VERSION 5.7 ;
  NOWIREEXTENSIONATPIN ON ;
  DIVIDERCHAR "/" ;
  BUSBITCHARS "[]" ;
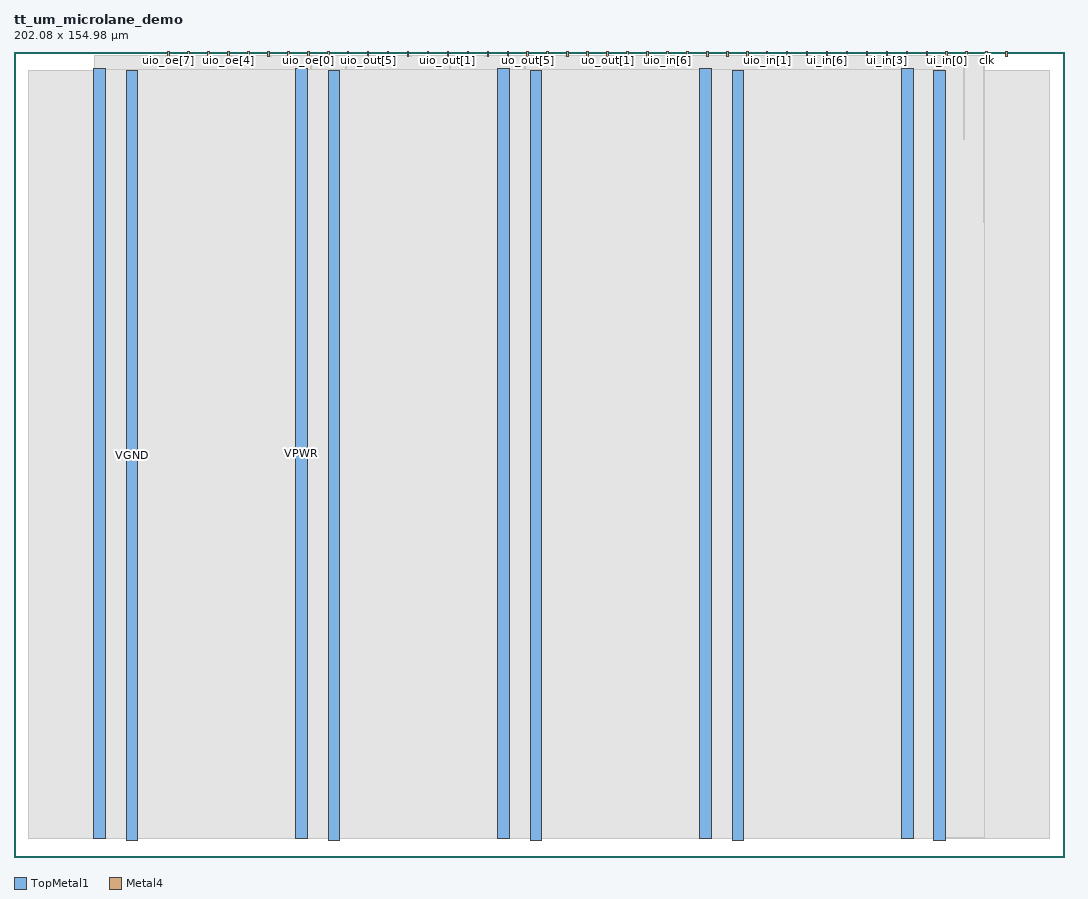
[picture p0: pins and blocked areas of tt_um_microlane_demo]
MACRO tt_um_microlane_demo
  CLASS BLOCK ;
  FOREIGN tt_um_microlane_demo ;
  ORIGIN 0.000 0.000 ;
  SIZE 202.080 BY 154.980 ;
  PIN VPWR
    DIRECTION INOUT ;
    USE POWER ;
    PORT
      LAYER TopMetal1 ;
        RECT 15.380 3.560 17.580 151.830 ;
    END
    PORT
      LAYER TopMetal1 ;
        RECT 54.250 3.560 56.450 151.830 ;
    END
    PORT
      LAYER TopMetal1 ;
        RECT 93.120 3.560 95.320 151.830 ;
    END
    PORT
      LAYER TopMetal1 ;
        RECT 131.990 3.560 134.190 151.830 ;
    END
    PORT
      LAYER TopMetal1 ;
        RECT 170.860 3.560 173.060 151.830 ;
    END
  END VPWR
  PIN VGND
    DIRECTION INOUT ;
    USE GROUND ;
    PORT
      LAYER TopMetal1 ;
        RECT 21.580 3.150 23.780 151.420 ;
    END
    PORT
      LAYER TopMetal1 ;
        RECT 60.450 3.150 62.650 151.420 ;
    END
    PORT
      LAYER TopMetal1 ;
        RECT 99.320 3.150 101.520 151.420 ;
    END
    PORT
      LAYER TopMetal1 ;
        RECT 138.190 3.150 140.390 151.420 ;
    END
    PORT
      LAYER TopMetal1 ;
        RECT 177.060 3.150 179.260 151.420 ;
    END
  END VGND
  PIN ena
    DIRECTION INPUT ;
    USE SIGNAL ;
    PORT
      LAYER Metal4 ;
        RECT 190.890 153.980 191.190 154.980 ;
    END
  END ena
  PIN clk
    DIRECTION INPUT ;
    USE SIGNAL ;
    PORT
      LAYER Metal4 ;
        RECT 187.050 153.980 187.350 154.980 ;
    END
  END clk
  PIN rst_n
    DIRECTION INPUT ;
    USE SIGNAL ;
    PORT
      LAYER Metal4 ;
        RECT 183.210 153.980 183.510 154.980 ;
    END
  END rst_n
  PIN ui_in[0]
    DIRECTION INPUT ;
    USE SIGNAL ;
    PORT
      LAYER Metal4 ;
        RECT 179.370 153.980 179.670 154.980 ;
    END
  END ui_in[0]
  PIN ui_in[1]
    DIRECTION INPUT ;
    USE SIGNAL ;
    PORT
      LAYER Metal4 ;
        RECT 175.530 153.980 175.830 154.980 ;
    END
  END ui_in[1]
  PIN ui_in[2]
    DIRECTION INPUT ;
    USE SIGNAL ;
    PORT
      LAYER Metal4 ;
        RECT 171.690 153.980 171.990 154.980 ;
    END
  END ui_in[2]
  PIN ui_in[3]
    DIRECTION INPUT ;
    USE SIGNAL ;
    PORT
      LAYER Metal4 ;
        RECT 167.850 153.980 168.150 154.980 ;
    END
  END ui_in[3]
  PIN ui_in[4]
    DIRECTION INPUT ;
    USE SIGNAL ;
    PORT
      LAYER Metal4 ;
        RECT 164.010 153.980 164.310 154.980 ;
    END
  END ui_in[4]
  PIN ui_in[5]
    DIRECTION INPUT ;
    USE SIGNAL ;
    PORT
      LAYER Metal4 ;
        RECT 160.170 153.980 160.470 154.980 ;
    END
  END ui_in[5]
  PIN ui_in[6]
    DIRECTION INPUT ;
    USE SIGNAL ;
    PORT
      LAYER Metal4 ;
        RECT 156.330 153.980 156.630 154.980 ;
    END
  END ui_in[6]
  PIN ui_in[7]
    DIRECTION INPUT ;
    USE SIGNAL ;
    PORT
      LAYER Metal4 ;
        RECT 152.490 153.980 152.790 154.980 ;
    END
  END ui_in[7]
  PIN uio_in[0]
    DIRECTION INPUT ;
    USE SIGNAL ;
    PORT
      LAYER Metal4 ;
        RECT 148.650 153.980 148.950 154.980 ;
    END
  END uio_in[0]
  PIN uio_in[1]
    DIRECTION INPUT ;
    USE SIGNAL ;
    PORT
      LAYER Metal4 ;
        RECT 144.810 153.980 145.110 154.980 ;
    END
  END uio_in[1]
  PIN uio_in[2]
    DIRECTION INPUT ;
    USE SIGNAL ;
    PORT
      LAYER Metal4 ;
        RECT 140.970 153.980 141.270 154.980 ;
    END
  END uio_in[2]
  PIN uio_in[3]
    DIRECTION INPUT ;
    USE SIGNAL ;
    PORT
      LAYER Metal4 ;
        RECT 137.130 153.980 137.430 154.980 ;
    END
  END uio_in[3]
  PIN uio_in[4]
    DIRECTION INPUT ;
    USE SIGNAL ;
    PORT
      LAYER Metal4 ;
        RECT 133.290 153.980 133.590 154.980 ;
    END
  END uio_in[4]
  PIN uio_in[5]
    DIRECTION INPUT ;
    USE SIGNAL ;
    PORT
      LAYER Metal4 ;
        RECT 129.450 153.980 129.750 154.980 ;
    END
  END uio_in[5]
  PIN uio_in[6]
    DIRECTION INPUT ;
    USE SIGNAL ;
    PORT
      LAYER Metal4 ;
        RECT 125.610 153.980 125.910 154.980 ;
    END
  END uio_in[6]
  PIN uio_in[7]
    DIRECTION INPUT ;
    USE SIGNAL ;
    PORT
      LAYER Metal4 ;
        RECT 121.770 153.980 122.070 154.980 ;
    END
  END uio_in[7]
  PIN uo_out[0]
    DIRECTION OUTPUT ;
    USE SIGNAL ;
    PORT
      LAYER Metal4 ;
        RECT 117.930 153.980 118.230 154.980 ;
    END
  END uo_out[0]
  PIN uo_out[1]
    DIRECTION OUTPUT ;
    USE SIGNAL ;
    PORT
      LAYER Metal4 ;
        RECT 114.090 153.980 114.390 154.980 ;
    END
  END uo_out[1]
  PIN uo_out[2]
    DIRECTION OUTPUT ;
    USE SIGNAL ;
    PORT
      LAYER Metal4 ;
        RECT 110.250 153.980 110.550 154.980 ;
    END
  END uo_out[2]
  PIN uo_out[3]
    DIRECTION OUTPUT ;
    USE SIGNAL ;
    PORT
      LAYER Metal4 ;
        RECT 106.410 153.980 106.710 154.980 ;
    END
  END uo_out[3]
  PIN uo_out[4]
    DIRECTION OUTPUT ;
    USE SIGNAL ;
    PORT
      LAYER Metal4 ;
        RECT 102.570 153.980 102.870 154.980 ;
    END
  END uo_out[4]
  PIN uo_out[5]
    DIRECTION OUTPUT ;
    USE SIGNAL ;
    PORT
      LAYER Metal4 ;
        RECT 98.730 153.980 99.030 154.980 ;
    END
  END uo_out[5]
  PIN uo_out[6]
    DIRECTION OUTPUT ;
    USE SIGNAL ;
    PORT
      LAYER Metal4 ;
        RECT 94.890 153.980 95.190 154.980 ;
    END
  END uo_out[6]
  PIN uo_out[7]
    DIRECTION OUTPUT ;
    USE SIGNAL ;
    PORT
      LAYER Metal4 ;
        RECT 91.050 153.980 91.350 154.980 ;
    END
  END uo_out[7]
  PIN uio_out[0]
    DIRECTION OUTPUT ;
    USE SIGNAL ;
    PORT
      LAYER Metal4 ;
        RECT 87.210 153.980 87.510 154.980 ;
    END
  END uio_out[0]
  PIN uio_out[1]
    DIRECTION OUTPUT ;
    USE SIGNAL ;
    PORT
      LAYER Metal4 ;
        RECT 83.370 153.980 83.670 154.980 ;
    END
  END uio_out[1]
  PIN uio_out[2]
    DIRECTION OUTPUT ;
    USE SIGNAL ;
    PORT
      LAYER Metal4 ;
        RECT 79.530 153.980 79.830 154.980 ;
    END
  END uio_out[2]
  PIN uio_out[3]
    DIRECTION OUTPUT ;
    USE SIGNAL ;
    PORT
      LAYER Metal4 ;
        RECT 75.690 153.980 75.990 154.980 ;
    END
  END uio_out[3]
  PIN uio_out[4]
    DIRECTION OUTPUT ;
    USE SIGNAL ;
    PORT
      LAYER Metal4 ;
        RECT 71.850 153.980 72.150 154.980 ;
    END
  END uio_out[4]
  PIN uio_out[5]
    DIRECTION OUTPUT ;
    USE SIGNAL ;
    PORT
      LAYER Metal4 ;
        RECT 68.010 153.980 68.310 154.980 ;
    END
  END uio_out[5]
  PIN uio_out[6]
    DIRECTION OUTPUT ;
    USE SIGNAL ;
    PORT
      LAYER Metal4 ;
        RECT 64.170 153.980 64.470 154.980 ;
    END
  END uio_out[6]
  PIN uio_out[7]
    DIRECTION OUTPUT ;
    USE SIGNAL ;
    PORT
      LAYER Metal4 ;
        RECT 60.330 153.980 60.630 154.980 ;
    END
  END uio_out[7]
  PIN uio_oe[0]
    DIRECTION OUTPUT ;
    USE SIGNAL ;
    PORT
      LAYER Metal4 ;
        RECT 56.490 153.980 56.790 154.980 ;
    END
  END uio_oe[0]
  PIN uio_oe[1]
    DIRECTION OUTPUT ;
    USE SIGNAL ;
    PORT
      LAYER Metal4 ;
        RECT 52.650 153.980 52.950 154.980 ;
    END
  END uio_oe[1]
  PIN uio_oe[2]
    DIRECTION OUTPUT ;
    USE SIGNAL ;
    PORT
      LAYER Metal4 ;
        RECT 48.810 153.980 49.110 154.980 ;
    END
  END uio_oe[2]
  PIN uio_oe[3]
    DIRECTION OUTPUT ;
    USE SIGNAL ;
    PORT
      LAYER Metal4 ;
        RECT 44.970 153.980 45.270 154.980 ;
    END
  END uio_oe[3]
  PIN uio_oe[4]
    DIRECTION OUTPUT ;
    USE SIGNAL ;
    PORT
      LAYER Metal4 ;
        RECT 41.130 153.980 41.430 154.980 ;
    END
  END uio_oe[4]
  PIN uio_oe[5]
    DIRECTION OUTPUT ;
    USE SIGNAL ;
    PORT
      LAYER Metal4 ;
        RECT 37.290 153.980 37.590 154.980 ;
    END
  END uio_oe[5]
  PIN uio_oe[6]
    DIRECTION OUTPUT ;
    USE SIGNAL ;
    PORT
      LAYER Metal4 ;
        RECT 33.450 153.980 33.750 154.980 ;
    END
  END uio_oe[6]
  PIN uio_oe[7]
    DIRECTION OUTPUT ;
    USE SIGNAL ;
    PORT
      LAYER Metal4 ;
        RECT 29.610 153.980 29.910 154.980 ;
    END
  END uio_oe[7]
  OBS
      LAYER GatPoly ;
        RECT 2.880 3.630 199.200 151.350 ;
      LAYER Metal1 ;
        RECT 2.880 3.560 199.200 151.420 ;
      LAYER Metal2 ;
        RECT 15.560 3.635 179.080 154.285 ;
      LAYER Metal3 ;
        RECT 15.515 3.680 186.865 154.320 ;
      LAYER Metal4 ;
        RECT 15.560 7.415 17.400 7.705 ;
        RECT 54.430 7.415 56.270 7.705 ;
        RECT 93.300 7.415 95.140 7.705 ;
        RECT 132.170 7.415 134.010 7.705 ;
        RECT 171.040 7.415 172.880 7.705 ;
        RECT 15.560 14.975 17.400 15.265 ;
        RECT 54.430 14.975 56.270 15.265 ;
        RECT 93.300 14.975 95.140 15.265 ;
        RECT 132.170 14.975 134.010 15.265 ;
        RECT 171.040 14.975 172.880 15.265 ;
        RECT 15.560 22.535 17.400 22.825 ;
        RECT 54.430 22.535 56.270 22.825 ;
        RECT 93.300 22.535 95.140 22.825 ;
        RECT 132.170 22.535 134.010 22.825 ;
        RECT 171.040 22.535 172.880 22.825 ;
        RECT 15.560 30.095 17.400 30.385 ;
        RECT 54.430 30.095 56.270 30.385 ;
        RECT 93.300 30.095 95.140 30.385 ;
        RECT 132.170 30.095 134.010 30.385 ;
        RECT 171.040 30.095 172.880 30.385 ;
        RECT 15.560 37.655 17.400 37.945 ;
        RECT 54.430 37.655 56.270 37.945 ;
        RECT 93.300 37.655 95.140 37.945 ;
        RECT 132.170 37.655 134.010 37.945 ;
        RECT 171.040 37.655 172.880 37.945 ;
        RECT 15.560 45.215 17.400 45.505 ;
        RECT 54.430 45.215 56.270 45.505 ;
        RECT 93.300 45.215 95.140 45.505 ;
        RECT 132.170 45.215 134.010 45.505 ;
        RECT 171.040 45.215 172.880 45.505 ;
        RECT 15.560 52.775 17.400 53.065 ;
        RECT 54.430 52.775 56.270 53.065 ;
        RECT 93.300 52.775 95.140 53.065 ;
        RECT 132.170 52.775 134.010 53.065 ;
        RECT 171.040 52.775 172.880 53.065 ;
        RECT 15.560 60.335 17.400 60.625 ;
        RECT 54.430 60.335 56.270 60.625 ;
        RECT 93.300 60.335 95.140 60.625 ;
        RECT 132.170 60.335 134.010 60.625 ;
        RECT 171.040 60.335 172.880 60.625 ;
        RECT 15.560 67.895 17.400 68.185 ;
        RECT 54.430 67.895 56.270 68.185 ;
        RECT 93.300 67.895 95.140 68.185 ;
        RECT 132.170 67.895 134.010 68.185 ;
        RECT 171.040 67.895 172.880 68.185 ;
        RECT 15.560 75.455 17.400 75.745 ;
        RECT 54.430 75.455 56.270 75.745 ;
        RECT 93.300 75.455 95.140 75.745 ;
        RECT 132.170 75.455 134.010 75.745 ;
        RECT 171.040 75.455 172.880 75.745 ;
        RECT 15.560 83.015 17.400 83.305 ;
        RECT 54.430 83.015 56.270 83.305 ;
        RECT 93.300 83.015 95.140 83.305 ;
        RECT 132.170 83.015 134.010 83.305 ;
        RECT 171.040 83.015 172.880 83.305 ;
        RECT 15.560 90.575 17.400 90.865 ;
        RECT 54.430 90.575 56.270 90.865 ;
        RECT 93.300 90.575 95.140 90.865 ;
        RECT 132.170 90.575 134.010 90.865 ;
        RECT 171.040 90.575 172.880 90.865 ;
        RECT 15.560 98.135 17.400 98.425 ;
        RECT 54.430 98.135 56.270 98.425 ;
        RECT 93.300 98.135 95.140 98.425 ;
        RECT 132.170 98.135 134.010 98.425 ;
        RECT 171.040 98.135 172.880 98.425 ;
        RECT 15.560 105.695 17.400 105.985 ;
        RECT 54.430 105.695 56.270 105.985 ;
        RECT 93.300 105.695 95.140 105.985 ;
        RECT 132.170 105.695 134.010 105.985 ;
        RECT 171.040 105.695 172.880 105.985 ;
        RECT 15.560 113.255 17.400 113.545 ;
        RECT 54.430 113.255 56.270 113.545 ;
        RECT 93.300 113.255 95.140 113.545 ;
        RECT 132.170 113.255 134.010 113.545 ;
        RECT 171.040 113.255 172.880 113.545 ;
        RECT 15.560 120.815 17.400 121.105 ;
        RECT 54.430 120.815 56.270 121.105 ;
        RECT 93.300 120.815 95.140 121.105 ;
        RECT 132.170 120.815 134.010 121.105 ;
        RECT 171.040 120.815 172.880 121.105 ;
        RECT 15.560 128.375 17.400 128.665 ;
        RECT 54.430 128.375 56.270 128.665 ;
        RECT 93.300 128.375 95.140 128.665 ;
        RECT 132.170 128.375 134.010 128.665 ;
        RECT 171.040 128.375 172.880 128.665 ;
        RECT 15.560 135.935 17.400 136.225 ;
        RECT 54.430 135.935 56.270 136.225 ;
        RECT 93.300 135.935 95.140 136.225 ;
        RECT 132.170 135.935 134.010 136.225 ;
        RECT 171.040 135.935 172.880 136.225 ;
        RECT 15.560 143.495 17.400 143.785 ;
        RECT 54.430 143.495 56.270 143.785 ;
        RECT 93.300 143.495 95.140 143.785 ;
        RECT 132.170 143.495 134.010 143.785 ;
        RECT 171.040 143.495 172.880 143.785 ;
        RECT 15.560 151.055 17.400 151.345 ;
        RECT 54.430 151.055 56.270 151.345 ;
        RECT 93.300 151.055 95.140 151.345 ;
        RECT 132.170 151.055 134.010 151.345 ;
        RECT 171.040 151.055 172.880 151.345 ;
        RECT 21.760 3.635 23.600 3.925 ;
        RECT 60.630 3.635 62.470 3.925 ;
        RECT 99.500 3.635 101.340 3.925 ;
        RECT 138.370 3.635 140.210 3.925 ;
        RECT 177.240 3.635 179.080 3.925 ;
        RECT 21.760 11.195 23.600 11.485 ;
        RECT 60.630 11.195 62.470 11.485 ;
        RECT 99.500 11.195 101.340 11.485 ;
        RECT 138.370 11.195 140.210 11.485 ;
        RECT 177.240 11.195 179.080 11.485 ;
        RECT 21.760 18.755 23.600 19.045 ;
        RECT 60.630 18.755 62.470 19.045 ;
        RECT 99.500 18.755 101.340 19.045 ;
        RECT 138.370 18.755 140.210 19.045 ;
        RECT 177.240 18.755 179.080 19.045 ;
        RECT 21.760 26.315 23.600 26.605 ;
        RECT 60.630 26.315 62.470 26.605 ;
        RECT 99.500 26.315 101.340 26.605 ;
        RECT 138.370 26.315 140.210 26.605 ;
        RECT 177.240 26.315 179.080 26.605 ;
        RECT 21.760 33.875 23.600 34.165 ;
        RECT 60.630 33.875 62.470 34.165 ;
        RECT 99.500 33.875 101.340 34.165 ;
        RECT 138.370 33.875 140.210 34.165 ;
        RECT 177.240 33.875 179.080 34.165 ;
        RECT 21.760 41.435 23.600 41.725 ;
        RECT 60.630 41.435 62.470 41.725 ;
        RECT 99.500 41.435 101.340 41.725 ;
        RECT 138.370 41.435 140.210 41.725 ;
        RECT 177.240 41.435 179.080 41.725 ;
        RECT 21.760 48.995 23.600 49.285 ;
        RECT 60.630 48.995 62.470 49.285 ;
        RECT 99.500 48.995 101.340 49.285 ;
        RECT 138.370 48.995 140.210 49.285 ;
        RECT 177.240 48.995 179.080 49.285 ;
        RECT 21.760 56.555 23.600 56.845 ;
        RECT 60.630 56.555 62.470 56.845 ;
        RECT 99.500 56.555 101.340 56.845 ;
        RECT 138.370 56.555 140.210 56.845 ;
        RECT 177.240 56.555 179.080 56.845 ;
        RECT 21.760 64.115 23.600 64.405 ;
        RECT 60.630 64.115 62.470 64.405 ;
        RECT 99.500 64.115 101.340 64.405 ;
        RECT 138.370 64.115 140.210 64.405 ;
        RECT 177.240 64.115 179.080 64.405 ;
        RECT 21.760 71.675 23.600 71.965 ;
        RECT 60.630 71.675 62.470 71.965 ;
        RECT 99.500 71.675 101.340 71.965 ;
        RECT 138.370 71.675 140.210 71.965 ;
        RECT 177.240 71.675 179.080 71.965 ;
        RECT 21.760 79.235 23.600 79.525 ;
        RECT 60.630 79.235 62.470 79.525 ;
        RECT 99.500 79.235 101.340 79.525 ;
        RECT 138.370 79.235 140.210 79.525 ;
        RECT 177.240 79.235 179.080 79.525 ;
        RECT 21.760 86.795 23.600 87.085 ;
        RECT 60.630 86.795 62.470 87.085 ;
        RECT 99.500 86.795 101.340 87.085 ;
        RECT 138.370 86.795 140.210 87.085 ;
        RECT 177.240 86.795 179.080 87.085 ;
        RECT 21.760 94.355 23.600 94.645 ;
        RECT 60.630 94.355 62.470 94.645 ;
        RECT 99.500 94.355 101.340 94.645 ;
        RECT 138.370 94.355 140.210 94.645 ;
        RECT 177.240 94.355 179.080 94.645 ;
        RECT 21.760 101.915 23.600 102.205 ;
        RECT 60.630 101.915 62.470 102.205 ;
        RECT 99.500 101.915 101.340 102.205 ;
        RECT 138.370 101.915 140.210 102.205 ;
        RECT 177.240 101.915 179.080 102.205 ;
        RECT 21.760 109.475 23.600 109.765 ;
        RECT 60.630 109.475 62.470 109.765 ;
        RECT 99.500 109.475 101.340 109.765 ;
        RECT 138.370 109.475 140.210 109.765 ;
        RECT 177.240 109.475 179.080 109.765 ;
        RECT 21.760 117.035 23.600 117.325 ;
        RECT 60.630 117.035 62.470 117.325 ;
        RECT 99.500 117.035 101.340 117.325 ;
        RECT 138.370 117.035 140.210 117.325 ;
        RECT 177.240 117.035 179.080 117.325 ;
        RECT 21.760 124.595 23.600 124.885 ;
        RECT 60.630 124.595 62.470 124.885 ;
        RECT 99.500 124.595 101.340 124.885 ;
        RECT 138.370 124.595 140.210 124.885 ;
        RECT 177.240 124.595 179.080 124.885 ;
        RECT 21.760 132.155 23.600 132.445 ;
        RECT 60.630 132.155 62.470 132.445 ;
        RECT 99.500 132.155 101.340 132.445 ;
        RECT 138.370 132.155 140.210 132.445 ;
        RECT 177.240 132.155 179.080 132.445 ;
        RECT 21.760 139.715 23.600 140.005 ;
        RECT 60.630 139.715 62.470 140.005 ;
        RECT 99.500 139.715 101.340 140.005 ;
        RECT 138.370 139.715 140.210 140.005 ;
        RECT 177.240 139.715 179.080 140.005 ;
        RECT 21.760 147.275 23.600 147.565 ;
        RECT 60.630 147.275 62.470 147.565 ;
        RECT 99.500 147.275 101.340 147.565 ;
        RECT 138.370 147.275 140.210 147.565 ;
        RECT 177.240 147.275 179.080 147.565 ;
        RECT 190.890 153.980 191.190 154.980 ;
        RECT 187.050 153.980 187.350 154.980 ;
        RECT 183.210 153.980 183.510 154.980 ;
        RECT 179.370 153.980 179.670 154.980 ;
        RECT 175.530 153.980 175.830 154.980 ;
        RECT 171.690 153.980 171.990 154.980 ;
        RECT 167.850 153.980 168.150 154.980 ;
        RECT 164.010 153.980 164.310 154.980 ;
        RECT 160.170 153.980 160.470 154.980 ;
        RECT 156.330 153.980 156.630 154.980 ;
        RECT 152.490 153.980 152.790 154.980 ;
        RECT 148.650 153.980 148.950 154.980 ;
        RECT 144.810 153.980 145.110 154.980 ;
        RECT 140.970 153.980 141.270 154.980 ;
        RECT 137.130 153.980 137.430 154.980 ;
        RECT 133.290 153.980 133.590 154.980 ;
        RECT 129.450 153.980 129.750 154.980 ;
        RECT 125.610 153.980 125.910 154.980 ;
        RECT 121.770 153.980 122.070 154.980 ;
        RECT 117.930 153.980 118.230 154.980 ;
        RECT 114.090 153.980 114.390 154.980 ;
        RECT 110.250 153.980 110.550 154.980 ;
        RECT 106.410 153.980 106.710 154.980 ;
        RECT 102.570 153.980 102.870 154.980 ;
        RECT 98.730 153.980 99.030 154.980 ;
        RECT 94.890 153.980 95.190 154.980 ;
        RECT 91.050 153.980 91.350 154.980 ;
        RECT 87.210 153.980 87.510 154.980 ;
        RECT 83.370 153.980 83.670 154.980 ;
        RECT 79.530 153.980 79.830 154.980 ;
        RECT 75.690 153.980 75.990 154.980 ;
        RECT 71.850 153.980 72.150 154.980 ;
        RECT 68.010 153.980 68.310 154.980 ;
        RECT 64.170 153.980 64.470 154.980 ;
        RECT 60.330 153.980 60.630 154.980 ;
        RECT 56.490 153.980 56.790 154.980 ;
        RECT 52.650 153.980 52.950 154.980 ;
        RECT 48.810 153.980 49.110 154.980 ;
        RECT 44.970 153.980 45.270 154.980 ;
        RECT 41.130 153.980 41.430 154.980 ;
        RECT 37.290 153.980 37.590 154.980 ;
        RECT 33.450 153.980 33.750 154.980 ;
        RECT 29.610 153.980 29.910 154.980 ;
        RECT 110.780 134.255 110.980 134.545 ;
        RECT 110.780 117.455 110.980 117.745 ;
        RECT 110.780 117.500 110.980 117.700 ;
        RECT 110.780 117.500 110.980 134.500 ;
        RECT 110.780 134.300 110.980 134.500 ;
        RECT 105.020 141.815 105.220 142.105 ;
        RECT 105.020 124.595 105.220 124.885 ;
        RECT 105.020 124.640 105.220 124.840 ;
        RECT 105.020 124.640 105.220 142.060 ;
        RECT 105.020 141.860 105.220 142.060 ;
        RECT 97.820 134.255 98.020 134.545 ;
        RECT 97.820 132.155 98.020 132.445 ;
        RECT 97.820 132.200 98.020 132.400 ;
        RECT 97.820 132.200 98.020 134.500 ;
        RECT 97.820 134.300 98.020 134.500 ;
        RECT 81.500 27.155 81.700 27.445 ;
        RECT 81.500 27.200 81.700 27.400 ;
        RECT 81.500 27.200 81.700 44.620 ;
        RECT 81.500 33.035 81.700 33.325 ;
        RECT 81.500 33.080 81.700 33.280 ;
        RECT 81.500 44.375 81.700 44.665 ;
        RECT 81.500 44.420 81.700 44.620 ;
        RECT 137.660 34.715 137.860 35.005 ;
        RECT 137.660 33.035 137.860 33.325 ;
        RECT 137.660 33.080 137.860 33.280 ;
        RECT 137.660 33.080 137.860 34.960 ;
        RECT 137.660 34.760 137.860 34.960 ;
        RECT 82.940 35.555 83.140 35.845 ;
        RECT 82.940 32.195 83.140 32.485 ;
        RECT 82.940 32.240 83.140 32.440 ;
        RECT 82.940 32.240 83.140 35.800 ;
        RECT 82.940 35.600 83.140 35.800 ;
        RECT 140.540 35.555 140.740 35.845 ;
        RECT 140.540 35.600 140.740 35.800 ;
        RECT 140.540 35.600 140.740 42.520 ;
        RECT 140.540 42.275 140.740 42.565 ;
        RECT 140.540 42.320 140.740 42.520 ;
        RECT 104.540 35.975 104.740 36.265 ;
        RECT 104.540 34.715 104.740 35.005 ;
        RECT 104.540 34.760 104.740 34.960 ;
        RECT 104.540 34.760 104.740 36.220 ;
        RECT 104.540 36.020 104.740 36.220 ;
        RECT 80.540 28.415 80.740 28.705 ;
        RECT 80.540 27.155 80.740 27.445 ;
        RECT 80.540 27.200 80.740 27.400 ;
        RECT 80.540 27.200 80.740 28.660 ;
        RECT 80.540 28.460 80.740 28.660 ;
        RECT 113.660 43.115 113.860 43.405 ;
        RECT 113.660 43.160 113.860 43.360 ;
        RECT 113.660 43.160 113.860 45.460 ;
        RECT 113.660 45.215 113.860 45.505 ;
        RECT 113.660 45.260 113.860 45.460 ;
        RECT 137.180 59.075 137.380 59.365 ;
        RECT 137.180 56.555 137.380 56.845 ;
        RECT 137.180 56.600 137.380 56.800 ;
        RECT 137.180 56.600 137.380 59.320 ;
        RECT 137.180 59.120 137.380 59.320 ;
        RECT 91.580 43.115 91.780 43.405 ;
        RECT 91.580 40.595 91.780 40.885 ;
        RECT 91.580 40.640 91.780 40.840 ;
        RECT 91.580 40.640 91.780 43.360 ;
        RECT 91.580 43.160 91.780 43.360 ;
        RECT 91.580 43.160 91.780 59.320 ;
        RECT 91.580 59.075 91.780 59.365 ;
        RECT 91.580 59.120 91.780 59.320 ;
        RECT 136.700 43.115 136.900 43.405 ;
        RECT 136.700 33.875 136.900 34.165 ;
        RECT 136.700 33.920 136.900 34.120 ;
        RECT 136.700 33.920 136.900 43.360 ;
        RECT 136.700 40.595 136.900 40.885 ;
        RECT 136.700 40.640 136.900 40.840 ;
        RECT 136.700 43.160 136.900 43.360 ;
        RECT 122.780 43.115 122.980 43.405 ;
        RECT 122.780 43.160 122.980 43.360 ;
        RECT 122.780 43.160 122.980 45.460 ;
        RECT 122.780 45.215 122.980 45.505 ;
        RECT 122.780 45.260 122.980 45.460 ;
        RECT 127.100 50.675 127.300 50.965 ;
        RECT 127.100 50.720 127.300 50.920 ;
        RECT 127.100 50.720 127.300 53.860 ;
        RECT 127.100 53.615 127.300 53.905 ;
        RECT 127.100 53.660 127.300 53.860 ;
        RECT 150.140 59.075 150.340 59.365 ;
        RECT 150.140 49.835 150.340 50.125 ;
        RECT 150.140 49.880 150.340 50.080 ;
        RECT 150.140 49.880 150.340 59.320 ;
        RECT 150.140 53.615 150.340 53.905 ;
        RECT 150.140 53.660 150.340 53.860 ;
        RECT 150.140 59.120 150.340 59.320 ;
        RECT 122.780 80.915 122.980 81.205 ;
        RECT 122.780 80.960 122.980 81.160 ;
        RECT 122.780 80.960 122.980 86.200 ;
        RECT 122.780 85.955 122.980 86.245 ;
        RECT 122.780 86.000 122.980 86.200 ;
        RECT 117.980 111.155 118.180 111.445 ;
        RECT 117.980 109.055 118.180 109.345 ;
        RECT 117.980 109.100 118.180 109.300 ;
        RECT 117.980 109.100 118.180 111.400 ;
        RECT 117.980 111.200 118.180 111.400 ;
        RECT 120.860 43.115 121.060 43.405 ;
        RECT 120.860 41.855 121.060 42.145 ;
        RECT 120.860 41.900 121.060 42.100 ;
        RECT 120.860 41.900 121.060 43.360 ;
        RECT 120.860 43.160 121.060 43.360 ;
        RECT 120.860 43.160 121.060 44.620 ;
        RECT 120.860 44.375 121.060 44.665 ;
        RECT 120.860 44.420 121.060 44.620 ;
        RECT 64.700 96.035 64.900 96.325 ;
        RECT 64.700 96.080 64.900 96.280 ;
        RECT 64.700 96.080 64.900 98.380 ;
        RECT 64.700 98.135 64.900 98.425 ;
        RECT 64.700 98.180 64.900 98.380 ;
        RECT 101.660 88.475 101.860 88.765 ;
        RECT 101.660 80.915 101.860 81.205 ;
        RECT 101.660 80.960 101.860 81.160 ;
        RECT 101.660 80.960 101.860 88.720 ;
        RECT 101.660 88.520 101.860 88.720 ;
        RECT 101.660 88.520 101.860 95.440 ;
        RECT 101.660 95.195 101.860 95.485 ;
        RECT 101.660 95.240 101.860 95.440 ;
        RECT 131.420 88.895 131.620 89.185 ;
        RECT 131.420 88.940 131.620 89.140 ;
        RECT 131.420 88.940 131.620 91.660 ;
        RECT 131.420 91.415 131.620 91.705 ;
        RECT 131.420 91.460 131.620 91.660 ;
        RECT 72.860 58.235 73.060 58.525 ;
        RECT 72.860 41.855 73.060 42.145 ;
        RECT 72.860 41.900 73.060 42.100 ;
        RECT 72.860 41.900 73.060 58.480 ;
        RECT 72.860 58.280 73.060 58.480 ;
        RECT 72.860 58.280 73.060 63.520 ;
        RECT 72.860 63.275 73.060 63.565 ;
        RECT 72.860 63.320 73.060 63.520 ;
        RECT 88.700 35.555 88.900 35.845 ;
        RECT 88.700 35.600 88.900 35.800 ;
        RECT 88.700 35.600 88.900 38.740 ;
        RECT 88.700 38.495 88.900 38.785 ;
        RECT 88.700 38.540 88.900 38.740 ;
        RECT 103.100 65.795 103.300 66.085 ;
        RECT 103.100 57.815 103.300 58.105 ;
        RECT 103.100 57.860 103.300 58.060 ;
        RECT 103.100 57.860 103.300 66.040 ;
        RECT 103.100 63.275 103.300 63.565 ;
        RECT 103.100 63.320 103.300 63.520 ;
        RECT 103.100 65.840 103.300 66.040 ;
        RECT 103.100 65.840 103.300 68.560 ;
        RECT 103.100 68.315 103.300 68.605 ;
        RECT 103.100 68.360 103.300 68.560 ;
        RECT 83.420 43.115 83.620 43.405 ;
        RECT 83.420 43.160 83.620 43.360 ;
        RECT 83.420 43.160 83.620 45.460 ;
        RECT 83.420 45.215 83.620 45.505 ;
        RECT 83.420 45.260 83.620 45.460 ;
        RECT 113.180 81.755 113.380 82.045 ;
        RECT 113.180 76.295 113.380 76.585 ;
        RECT 113.180 76.340 113.380 76.540 ;
        RECT 113.180 76.340 113.380 82.000 ;
        RECT 113.180 81.800 113.380 82.000 ;
        RECT 146.780 81.755 146.980 82.045 ;
        RECT 146.780 64.115 146.980 64.405 ;
        RECT 146.780 64.160 146.980 64.360 ;
        RECT 146.780 64.160 146.980 82.000 ;
        RECT 146.780 76.295 146.980 76.585 ;
        RECT 146.780 76.340 146.980 76.540 ;
        RECT 146.780 81.800 146.980 82.000 ;
        RECT 102.140 50.675 102.340 50.965 ;
        RECT 102.140 50.720 102.340 50.920 ;
        RECT 102.140 50.720 102.340 53.440 ;
        RECT 102.140 53.195 102.340 53.485 ;
        RECT 102.140 53.240 102.340 53.440 ;
        RECT 102.140 53.240 102.340 55.960 ;
        RECT 102.140 55.715 102.340 56.005 ;
        RECT 102.140 55.760 102.340 55.960 ;
        RECT 95.420 43.115 95.620 43.405 ;
        RECT 95.420 43.160 95.620 43.360 ;
        RECT 95.420 43.160 95.620 47.140 ;
        RECT 95.420 46.895 95.620 47.185 ;
        RECT 95.420 46.940 95.620 47.140 ;
        RECT 121.820 89.315 122.020 89.605 ;
        RECT 121.820 77.135 122.020 77.425 ;
        RECT 121.820 77.180 122.020 77.380 ;
        RECT 121.820 77.180 122.020 89.560 ;
        RECT 121.820 89.360 122.020 89.560 ;
        RECT 138.140 74.195 138.340 74.485 ;
        RECT 138.140 72.515 138.340 72.805 ;
        RECT 138.140 72.560 138.340 72.760 ;
        RECT 138.140 72.560 138.340 74.440 ;
        RECT 138.140 74.240 138.340 74.440 ;
        RECT 138.140 74.240 138.340 77.380 ;
        RECT 138.140 77.135 138.340 77.425 ;
        RECT 138.140 77.180 138.340 77.380 ;
        RECT 145.820 65.795 146.020 66.085 ;
        RECT 145.820 65.840 146.020 66.040 ;
        RECT 145.820 65.840 146.020 67.300 ;
        RECT 145.820 67.055 146.020 67.345 ;
        RECT 145.820 67.100 146.020 67.300 ;
        RECT 52.220 42.695 52.420 42.985 ;
        RECT 52.220 42.740 52.420 42.940 ;
        RECT 52.220 42.740 52.420 45.040 ;
        RECT 52.220 44.795 52.420 45.085 ;
        RECT 52.220 44.840 52.420 45.040 ;
        RECT 92.540 20.015 92.740 20.305 ;
        RECT 92.540 20.060 92.740 20.260 ;
        RECT 92.540 20.060 92.740 23.620 ;
        RECT 92.540 23.375 92.740 23.665 ;
        RECT 92.540 23.420 92.740 23.620 ;
        RECT 106.460 50.675 106.660 50.965 ;
        RECT 106.460 50.720 106.660 50.920 ;
        RECT 106.460 50.720 106.660 54.700 ;
        RECT 106.460 54.455 106.660 54.745 ;
        RECT 106.460 54.500 106.660 54.700 ;
        RECT 87.260 74.195 87.460 74.485 ;
        RECT 87.260 69.995 87.460 70.285 ;
        RECT 87.260 70.040 87.460 70.240 ;
        RECT 87.260 70.040 87.460 74.440 ;
        RECT 87.260 74.240 87.460 74.440 ;
        RECT 87.260 74.240 87.460 82.000 ;
        RECT 87.260 81.755 87.460 82.045 ;
        RECT 87.260 81.800 87.460 82.000 ;
        RECT 144.860 74.195 145.060 74.485 ;
        RECT 144.860 55.295 145.060 55.585 ;
        RECT 144.860 55.340 145.060 55.540 ;
        RECT 144.860 55.340 145.060 74.440 ;
        RECT 144.860 69.995 145.060 70.285 ;
        RECT 144.860 70.040 145.060 70.240 ;
        RECT 144.860 74.240 145.060 74.440 ;
        RECT 143.900 58.655 144.100 58.945 ;
        RECT 143.900 58.700 144.100 58.900 ;
        RECT 143.900 58.700 144.100 75.700 ;
        RECT 143.900 75.455 144.100 75.745 ;
        RECT 143.900 75.500 144.100 75.700 ;
        RECT 50.300 50.675 50.500 50.965 ;
        RECT 50.300 42.275 50.500 42.565 ;
        RECT 50.300 42.320 50.500 42.520 ;
        RECT 50.300 42.320 50.500 50.920 ;
        RECT 50.300 50.720 50.500 50.920 ;
        RECT 50.300 50.720 50.500 58.480 ;
        RECT 50.300 58.235 50.500 58.525 ;
        RECT 50.300 58.280 50.500 58.480 ;
        RECT 94.460 51.515 94.660 51.805 ;
        RECT 94.460 47.735 94.660 48.025 ;
        RECT 94.460 47.780 94.660 47.980 ;
        RECT 94.460 47.780 94.660 51.760 ;
        RECT 94.460 51.560 94.660 51.760 ;
        RECT 120.860 82.175 121.060 82.465 ;
        RECT 120.860 47.735 121.060 48.025 ;
        RECT 120.860 47.780 121.060 47.980 ;
        RECT 120.860 47.780 121.060 82.420 ;
        RECT 120.860 82.220 121.060 82.420 ;
        RECT 111.740 58.235 111.940 58.525 ;
        RECT 111.740 19.595 111.940 19.885 ;
        RECT 111.740 19.640 111.940 19.840 ;
        RECT 111.740 19.640 111.940 58.480 ;
        RECT 111.740 58.280 111.940 58.480 ;
        RECT 119.900 65.795 120.100 66.085 ;
        RECT 119.900 65.840 120.100 66.040 ;
        RECT 119.900 65.840 120.100 68.140 ;
        RECT 119.900 67.895 120.100 68.185 ;
        RECT 119.900 67.940 120.100 68.140 ;
        RECT 29.180 50.675 29.380 50.965 ;
        RECT 29.180 50.720 29.380 50.920 ;
        RECT 29.180 50.720 29.380 62.680 ;
        RECT 29.180 62.435 29.380 62.725 ;
        RECT 29.180 62.480 29.380 62.680 ;
        RECT 131.420 58.235 131.620 58.525 ;
        RECT 131.420 38.075 131.620 38.365 ;
        RECT 131.420 38.120 131.620 38.320 ;
        RECT 131.420 38.120 131.620 58.480 ;
        RECT 131.420 58.280 131.620 58.480 ;
        RECT 131.420 58.280 131.620 60.580 ;
        RECT 131.420 60.335 131.620 60.625 ;
        RECT 131.420 60.380 131.620 60.580 ;
        RECT 95.420 50.675 95.620 50.965 ;
        RECT 95.420 50.720 95.620 50.920 ;
        RECT 95.420 50.720 95.620 59.740 ;
        RECT 95.420 59.495 95.620 59.785 ;
        RECT 95.420 59.540 95.620 59.740 ;
        RECT 95.420 59.540 95.620 71.080 ;
        RECT 95.420 70.835 95.620 71.125 ;
        RECT 95.420 70.880 95.620 71.080 ;
        RECT 141.500 58.235 141.700 58.525 ;
        RECT 141.500 50.675 141.700 50.965 ;
        RECT 141.500 50.720 141.700 50.920 ;
        RECT 141.500 50.720 141.700 58.480 ;
        RECT 141.500 58.280 141.700 58.480 ;
        RECT 141.500 58.280 141.700 61.420 ;
        RECT 141.500 61.175 141.700 61.465 ;
        RECT 141.500 61.220 141.700 61.420 ;
        RECT 137.180 66.635 137.380 66.925 ;
        RECT 137.180 62.435 137.380 62.725 ;
        RECT 137.180 62.480 137.380 62.680 ;
        RECT 137.180 62.480 137.380 66.880 ;
        RECT 137.180 66.680 137.380 66.880 ;
        RECT 134.300 73.355 134.500 73.645 ;
        RECT 134.300 69.155 134.500 69.445 ;
        RECT 134.300 69.200 134.500 69.400 ;
        RECT 134.300 69.200 134.500 73.600 ;
        RECT 134.300 73.400 134.500 73.600 ;
        RECT 33.500 50.675 33.700 50.965 ;
        RECT 33.500 50.720 33.700 50.920 ;
        RECT 33.500 50.720 33.700 69.400 ;
        RECT 33.500 69.155 33.700 69.445 ;
        RECT 33.500 69.200 33.700 69.400 ;
        RECT 128.060 35.555 128.260 35.845 ;
        RECT 128.060 27.575 128.260 27.865 ;
        RECT 128.060 27.620 128.260 27.820 ;
        RECT 128.060 27.620 128.260 35.800 ;
        RECT 128.060 35.600 128.260 35.800 ;
        RECT 128.060 35.600 128.260 66.040 ;
        RECT 128.060 65.795 128.260 66.085 ;
        RECT 128.060 65.840 128.260 66.040 ;
        RECT 135.740 35.555 135.940 35.845 ;
        RECT 135.740 35.600 135.940 35.800 ;
        RECT 135.740 35.600 135.940 52.180 ;
        RECT 135.740 51.935 135.940 52.225 ;
        RECT 135.740 51.980 135.940 52.180 ;
        RECT 40.220 73.355 40.420 73.645 ;
        RECT 40.220 57.395 40.420 57.685 ;
        RECT 40.220 57.440 40.420 57.640 ;
        RECT 40.220 57.440 40.420 73.600 ;
        RECT 40.220 73.400 40.420 73.600 ;
        RECT 40.220 73.400 40.420 76.960 ;
        RECT 40.220 76.715 40.420 77.005 ;
        RECT 40.220 76.760 40.420 76.960 ;
        RECT 105.980 73.355 106.180 73.645 ;
        RECT 105.980 73.400 106.180 73.600 ;
        RECT 105.980 73.400 106.180 76.960 ;
        RECT 105.980 76.715 106.180 77.005 ;
        RECT 105.980 76.760 106.180 76.960 ;
        RECT 105.980 76.760 106.180 80.320 ;
        RECT 105.980 80.075 106.180 80.365 ;
        RECT 105.980 80.120 106.180 80.320 ;
        RECT 68.060 50.675 68.260 50.965 ;
        RECT 68.060 50.720 68.260 50.920 ;
        RECT 68.060 50.720 68.260 53.020 ;
        RECT 68.060 52.775 68.260 53.065 ;
        RECT 68.060 52.820 68.260 53.020 ;
        RECT 45.500 73.355 45.700 73.645 ;
        RECT 45.500 40.595 45.700 40.885 ;
        RECT 45.500 40.640 45.700 40.840 ;
        RECT 45.500 40.640 45.700 73.600 ;
        RECT 45.500 73.400 45.700 73.600 ;
        RECT 45.500 73.400 45.700 80.320 ;
        RECT 45.500 80.075 45.700 80.365 ;
        RECT 45.500 80.120 45.700 80.320 ;
        RECT 101.660 35.555 101.860 35.845 ;
        RECT 101.660 35.600 101.860 35.800 ;
        RECT 101.660 35.600 101.860 39.580 ;
        RECT 101.660 39.335 101.860 39.625 ;
        RECT 101.660 39.380 101.860 39.580 ;
        RECT 41.180 58.235 41.380 58.525 ;
        RECT 41.180 58.280 41.380 58.480 ;
        RECT 41.180 58.280 41.380 60.580 ;
        RECT 41.180 60.335 41.380 60.625 ;
        RECT 41.180 60.380 41.380 60.580 ;
        RECT 46.940 80.915 47.140 81.205 ;
        RECT 46.940 80.960 47.140 81.160 ;
        RECT 46.940 80.960 47.140 85.360 ;
        RECT 46.940 85.115 47.140 85.405 ;
        RECT 46.940 85.160 47.140 85.360 ;
        RECT 96.380 65.795 96.580 66.085 ;
        RECT 96.380 50.255 96.580 50.545 ;
        RECT 96.380 50.300 96.580 50.500 ;
        RECT 96.380 50.300 96.580 66.040 ;
        RECT 96.380 65.840 96.580 66.040 ;
        RECT 96.380 65.840 96.580 75.280 ;
        RECT 96.380 75.035 96.580 75.325 ;
        RECT 96.380 75.080 96.580 75.280 ;
        RECT 106.940 80.915 107.140 81.205 ;
        RECT 106.940 80.960 107.140 81.160 ;
        RECT 106.940 80.960 107.140 85.360 ;
        RECT 106.940 85.115 107.140 85.405 ;
        RECT 106.940 85.160 107.140 85.360 ;
        RECT 106.460 43.115 106.660 43.405 ;
        RECT 106.460 43.160 106.660 43.360 ;
        RECT 106.460 43.160 106.660 45.460 ;
        RECT 106.460 45.215 106.660 45.505 ;
        RECT 106.460 45.260 106.660 45.460 ;
        RECT 115.100 73.355 115.300 73.645 ;
        RECT 115.100 73.400 115.300 73.600 ;
        RECT 115.100 73.400 115.300 78.640 ;
        RECT 115.100 78.395 115.300 78.685 ;
        RECT 115.100 78.440 115.300 78.640 ;
        RECT 94.390 73.285 94.730 73.715 ;
        RECT 94.385 73.285 94.735 73.715 ;
        RECT 94.380 73.320 94.740 73.680 ;
        RECT 100.215 73.355 100.425 73.645 ;
        RECT 100.220 73.400 100.420 73.600 ;
        RECT 100.220 73.400 100.420 74.860 ;
        RECT 100.220 74.615 100.420 74.905 ;
        RECT 100.220 74.660 100.420 74.860 ;
        RECT 44.540 58.235 44.740 58.525 ;
        RECT 44.540 58.280 44.740 58.480 ;
        RECT 44.540 58.280 44.740 78.640 ;
        RECT 44.540 78.395 44.740 78.685 ;
        RECT 44.540 78.440 44.740 78.640 ;
        RECT 88.220 65.795 88.420 66.085 ;
        RECT 88.220 65.840 88.420 66.040 ;
        RECT 88.220 65.840 88.420 79.480 ;
        RECT 88.220 79.235 88.420 79.525 ;
        RECT 88.220 79.280 88.420 79.480 ;
        RECT 95.420 88.475 95.620 88.765 ;
        RECT 95.420 79.235 95.620 79.525 ;
        RECT 95.420 79.280 95.620 79.480 ;
        RECT 95.420 79.280 95.620 88.720 ;
        RECT 95.420 88.520 95.620 88.720 ;
        RECT 77.660 73.355 77.860 73.645 ;
        RECT 77.660 73.400 77.860 73.600 ;
        RECT 77.660 73.400 77.860 77.800 ;
        RECT 77.660 77.555 77.860 77.845 ;
        RECT 77.660 77.600 77.860 77.800 ;
        RECT 76.700 65.375 76.900 65.665 ;
        RECT 76.700 65.420 76.900 65.620 ;
        RECT 76.700 65.420 76.900 76.120 ;
        RECT 76.700 75.875 76.900 76.165 ;
        RECT 76.700 75.920 76.900 76.120 ;
        RECT 100.150 43.885 100.490 44.315 ;
        RECT 100.145 43.885 100.495 44.315 ;
        RECT 100.140 43.920 100.500 44.280 ;
        RECT 107.415 43.955 107.625 44.245 ;
        RECT 107.420 44.000 107.620 44.200 ;
        RECT 107.420 44.000 107.620 44.620 ;
        RECT 107.420 44.375 107.620 44.665 ;
        RECT 107.420 44.420 107.620 44.620 ;
        RECT 97.820 58.235 98.020 58.525 ;
        RECT 97.815 49.835 98.025 50.125 ;
        RECT 97.820 49.880 98.020 50.080 ;
        RECT 97.820 49.880 98.020 58.480 ;
        RECT 97.820 58.280 98.020 58.480 ;
        RECT 101.655 49.835 101.865 50.125 ;
        RECT 101.660 44.375 101.860 44.665 ;
        RECT 101.660 44.420 101.860 44.620 ;
        RECT 101.660 44.420 101.860 50.080 ;
        RECT 101.660 49.880 101.860 50.080 ;
        RECT 83.900 80.915 84.100 81.205 ;
        RECT 83.900 64.115 84.100 64.405 ;
        RECT 83.900 64.160 84.100 64.360 ;
        RECT 83.900 64.160 84.100 81.160 ;
        RECT 83.900 80.960 84.100 81.160 ;
        RECT 83.900 80.960 84.100 87.880 ;
        RECT 83.900 87.635 84.100 87.925 ;
        RECT 83.900 87.680 84.100 87.880 ;
        RECT 78.620 43.115 78.820 43.405 ;
        RECT 78.620 43.160 78.820 43.360 ;
        RECT 78.620 43.160 78.820 95.440 ;
        RECT 78.620 95.195 78.820 95.485 ;
        RECT 78.620 95.240 78.820 95.440 ;
        RECT 91.100 104.435 91.300 104.725 ;
        RECT 91.100 100.235 91.300 100.525 ;
        RECT 91.100 100.280 91.300 100.480 ;
        RECT 91.100 100.280 91.300 104.680 ;
        RECT 91.100 104.480 91.300 104.680 ;
        RECT 112.220 104.435 112.420 104.725 ;
        RECT 112.220 100.235 112.420 100.525 ;
        RECT 112.220 100.280 112.420 100.480 ;
        RECT 112.220 100.280 112.420 104.680 ;
        RECT 112.220 104.480 112.420 104.680 ;
        RECT 87.260 103.595 87.460 103.885 ;
        RECT 87.260 103.640 87.460 103.840 ;
        RECT 87.260 103.640 87.460 105.940 ;
        RECT 87.260 105.695 87.460 105.985 ;
        RECT 87.260 105.740 87.460 105.940 ;
        RECT 42.140 88.475 42.340 88.765 ;
        RECT 42.140 88.520 42.340 88.720 ;
        RECT 42.140 88.520 42.340 103.000 ;
        RECT 42.140 102.755 42.340 103.045 ;
        RECT 42.140 102.800 42.340 103.000 ;
        RECT 73.340 88.475 73.540 88.765 ;
        RECT 73.340 85.955 73.540 86.245 ;
        RECT 73.340 86.000 73.540 86.200 ;
        RECT 73.340 86.000 73.540 88.720 ;
        RECT 73.340 88.520 73.540 88.720 ;
        RECT 73.340 88.520 73.540 103.000 ;
        RECT 73.340 102.755 73.540 103.045 ;
        RECT 73.340 102.800 73.540 103.000 ;
        RECT 83.420 96.035 83.620 96.325 ;
        RECT 83.420 96.080 83.620 96.280 ;
        RECT 83.420 96.080 83.620 109.300 ;
        RECT 83.420 102.755 83.620 103.045 ;
        RECT 83.420 102.800 83.620 103.000 ;
        RECT 83.420 109.055 83.620 109.345 ;
        RECT 83.420 109.100 83.620 109.300 ;
        RECT 121.820 104.435 122.020 104.725 ;
        RECT 121.820 98.135 122.020 98.425 ;
        RECT 121.820 98.180 122.020 98.380 ;
        RECT 121.820 98.180 122.020 104.680 ;
        RECT 121.820 104.480 122.020 104.680 ;
        RECT 114.620 96.035 114.820 96.325 ;
        RECT 114.620 96.080 114.820 96.280 ;
        RECT 114.620 96.080 114.820 99.220 ;
        RECT 114.620 98.975 114.820 99.265 ;
        RECT 114.620 99.020 114.820 99.220 ;
        RECT 77.660 88.475 77.860 88.765 ;
        RECT 77.660 86.795 77.860 87.085 ;
        RECT 77.660 86.840 77.860 87.040 ;
        RECT 77.660 86.840 77.860 88.720 ;
        RECT 77.660 88.520 77.860 88.720 ;
        RECT 77.660 88.520 77.860 93.760 ;
        RECT 77.660 93.515 77.860 93.805 ;
        RECT 77.660 93.560 77.860 93.760 ;
        RECT 76.700 96.875 76.900 97.165 ;
        RECT 76.700 85.955 76.900 86.245 ;
        RECT 76.700 86.000 76.900 86.200 ;
        RECT 76.700 86.000 76.900 97.120 ;
        RECT 76.700 96.920 76.900 97.120 ;
        RECT 76.700 96.920 76.900 99.640 ;
        RECT 76.700 99.395 76.900 99.685 ;
        RECT 76.700 99.440 76.900 99.640 ;
        RECT 72.380 96.035 72.580 96.325 ;
        RECT 72.380 96.080 72.580 96.280 ;
        RECT 72.380 96.080 72.580 98.380 ;
        RECT 72.380 98.135 72.580 98.425 ;
        RECT 72.380 98.180 72.580 98.380 ;
        RECT 136.700 89.315 136.900 89.605 ;
        RECT 136.700 86.795 136.900 87.085 ;
        RECT 136.700 86.840 136.900 87.040 ;
        RECT 136.700 86.840 136.900 89.560 ;
        RECT 136.700 89.360 136.900 89.560 ;
        RECT 126.550 95.965 126.890 96.395 ;
        RECT 126.545 95.965 126.895 96.395 ;
        RECT 126.540 96.000 126.900 96.360 ;
        RECT 132.855 96.035 133.065 96.325 ;
        RECT 132.860 96.080 133.060 96.280 ;
        RECT 132.860 96.080 133.060 97.540 ;
        RECT 132.860 97.295 133.060 97.585 ;
        RECT 132.860 97.340 133.060 97.540 ;
        RECT 141.020 88.475 141.220 88.765 ;
        RECT 141.020 85.955 141.220 86.245 ;
        RECT 141.020 86.000 141.220 86.200 ;
        RECT 141.020 86.000 141.220 88.720 ;
        RECT 141.020 88.520 141.220 88.720 ;
        RECT 69.020 103.595 69.220 103.885 ;
        RECT 69.020 90.575 69.220 90.865 ;
        RECT 69.020 90.620 69.220 90.820 ;
        RECT 69.020 90.620 69.220 103.840 ;
        RECT 69.020 103.640 69.220 103.840 ;
        RECT 69.020 103.640 69.220 106.360 ;
        RECT 69.020 106.115 69.220 106.405 ;
        RECT 69.020 106.160 69.220 106.360 ;
        RECT 86.230 95.965 86.570 96.395 ;
        RECT 86.225 95.965 86.575 96.395 ;
        RECT 86.220 96.000 86.580 96.360 ;
        RECT 88.695 96.035 88.905 96.325 ;
        RECT 88.700 96.080 88.900 96.280 ;
        RECT 88.700 96.080 88.900 97.540 ;
        RECT 88.700 97.295 88.900 97.585 ;
        RECT 88.700 97.340 88.900 97.540 ;
        RECT 67.580 111.995 67.780 112.285 ;
        RECT 67.580 110.315 67.780 110.605 ;
        RECT 67.580 110.360 67.780 110.560 ;
        RECT 67.580 110.360 67.780 112.240 ;
        RECT 67.580 112.040 67.780 112.240 ;
        RECT 39.260 66.635 39.460 66.925 ;
        RECT 39.260 66.680 39.460 66.880 ;
        RECT 39.260 66.680 39.460 90.400 ;
        RECT 39.260 90.155 39.460 90.445 ;
        RECT 39.260 90.200 39.460 90.400 ;
        RECT 82.460 80.915 82.660 81.205 ;
        RECT 82.460 80.960 82.660 81.160 ;
        RECT 82.460 80.960 82.660 97.540 ;
        RECT 82.460 97.295 82.660 97.585 ;
        RECT 82.460 97.340 82.660 97.540 ;
        RECT 57.020 80.915 57.220 81.205 ;
        RECT 57.020 80.960 57.220 81.160 ;
        RECT 57.020 80.960 57.220 83.260 ;
        RECT 57.020 83.015 57.220 83.305 ;
        RECT 57.020 83.060 57.220 83.260 ;
        RECT 46.940 95.195 47.140 95.485 ;
        RECT 46.940 95.240 47.140 95.440 ;
        RECT 46.940 95.240 47.140 105.100 ;
        RECT 46.940 104.855 47.140 105.145 ;
        RECT 46.940 104.900 47.140 105.100 ;
        RECT 90.140 88.895 90.340 89.185 ;
        RECT 90.140 88.940 90.340 89.140 ;
        RECT 90.140 88.940 90.340 100.480 ;
        RECT 90.140 100.235 90.340 100.525 ;
        RECT 90.140 100.280 90.340 100.480 ;
        RECT 57.500 89.315 57.700 89.605 ;
        RECT 57.500 89.360 57.700 89.560 ;
        RECT 57.500 89.360 57.700 97.540 ;
        RECT 57.500 97.295 57.700 97.585 ;
        RECT 57.500 97.340 57.700 97.540 ;
        RECT 45.980 89.735 46.180 90.025 ;
        RECT 45.980 89.780 46.180 89.980 ;
        RECT 45.980 89.780 46.180 97.540 ;
        RECT 45.980 97.295 46.180 97.585 ;
        RECT 45.980 97.340 46.180 97.540 ;
        RECT 98.780 64.955 98.980 65.245 ;
        RECT 98.780 65.000 98.980 65.200 ;
        RECT 98.780 65.000 98.980 82.420 ;
        RECT 98.780 82.175 98.980 82.465 ;
        RECT 98.780 82.220 98.980 82.420 ;
        RECT 77.655 80.915 77.865 81.205 ;
        RECT 77.660 80.960 77.860 81.160 ;
        RECT 77.660 80.960 77.860 82.420 ;
        RECT 77.660 82.175 77.860 82.465 ;
        RECT 77.660 82.220 77.860 82.420 ;
        RECT 105.430 80.845 105.770 81.275 ;
        RECT 105.425 80.845 105.775 81.275 ;
        RECT 105.420 80.880 105.780 81.240 ;
        RECT 97.815 59.075 98.025 59.365 ;
        RECT 97.820 59.120 98.020 59.320 ;
        RECT 97.820 59.120 98.020 67.300 ;
        RECT 97.820 67.055 98.020 67.345 ;
        RECT 97.820 67.100 98.020 67.300 ;
        RECT 98.780 35.975 98.980 36.265 ;
        RECT 98.775 59.075 98.985 59.365 ;
        RECT 98.780 36.020 98.980 36.220 ;
        RECT 98.780 36.020 98.980 59.320 ;
        RECT 98.780 59.120 98.980 59.320 ;
        RECT 39.260 43.955 39.460 44.245 ;
        RECT 39.260 44.000 39.460 44.200 ;
        RECT 39.260 44.000 39.460 59.740 ;
        RECT 39.260 59.495 39.460 59.785 ;
        RECT 39.260 59.540 39.460 59.740 ;
        RECT 48.380 75.875 48.580 76.165 ;
        RECT 48.380 75.920 48.580 76.120 ;
        RECT 48.380 75.920 48.580 90.400 ;
        RECT 48.380 90.155 48.580 90.445 ;
        RECT 48.380 90.200 48.580 90.400 ;
        RECT 107.900 77.555 108.100 77.845 ;
        RECT 107.900 77.600 108.100 77.800 ;
        RECT 107.900 77.600 108.100 89.980 ;
        RECT 107.900 89.735 108.100 90.025 ;
        RECT 107.900 89.780 108.100 89.980 ;
        RECT 119.900 35.555 120.100 35.845 ;
        RECT 119.900 35.600 120.100 35.800 ;
        RECT 119.900 35.600 120.100 52.180 ;
        RECT 119.900 51.935 120.100 52.225 ;
        RECT 119.900 51.980 120.100 52.180 ;
        RECT 35.420 74.195 35.620 74.485 ;
        RECT 35.420 74.240 35.620 74.440 ;
        RECT 35.420 74.240 35.620 82.420 ;
        RECT 35.420 82.175 35.620 82.465 ;
        RECT 35.420 82.220 35.620 82.420 ;
        RECT 32.540 51.515 32.740 51.805 ;
        RECT 32.540 51.560 32.740 51.760 ;
        RECT 32.540 51.560 32.740 59.740 ;
        RECT 32.540 59.495 32.740 59.785 ;
        RECT 32.540 59.540 32.740 59.740 ;
        RECT 132.860 78.395 133.060 78.685 ;
        RECT 132.860 78.440 133.060 78.640 ;
        RECT 132.860 78.440 133.060 82.420 ;
        RECT 132.860 82.175 133.060 82.465 ;
        RECT 132.860 82.220 133.060 82.420 ;
        RECT 110.300 71.675 110.500 71.965 ;
        RECT 110.300 71.720 110.500 71.920 ;
        RECT 110.300 71.720 110.500 74.860 ;
        RECT 110.300 74.615 110.500 74.905 ;
        RECT 110.300 74.660 110.500 74.860 ;
        RECT 42.620 52.775 42.820 53.065 ;
        RECT 42.620 52.820 42.820 53.020 ;
        RECT 42.620 52.820 42.820 68.140 ;
        RECT 42.620 67.895 42.820 68.185 ;
        RECT 42.620 67.940 42.820 68.140 ;
        RECT 111.740 59.075 111.940 59.365 ;
        RECT 111.740 59.120 111.940 59.320 ;
        RECT 111.740 59.120 111.940 67.300 ;
        RECT 111.740 67.055 111.940 67.345 ;
        RECT 111.740 67.100 111.940 67.300 ;
        RECT 107.900 55.715 108.100 56.005 ;
        RECT 107.900 55.760 108.100 55.960 ;
        RECT 107.900 55.760 108.100 59.740 ;
        RECT 107.900 59.495 108.100 59.785 ;
        RECT 107.900 59.540 108.100 59.740 ;
        RECT 52.700 66.635 52.900 66.925 ;
        RECT 52.700 57.395 52.900 57.685 ;
        RECT 52.700 57.440 52.900 57.640 ;
        RECT 52.700 57.440 52.900 66.880 ;
        RECT 52.700 66.680 52.900 66.880 ;
        RECT 124.220 65.795 124.420 66.085 ;
        RECT 124.220 61.175 124.420 61.465 ;
        RECT 124.220 61.220 124.420 61.420 ;
        RECT 124.220 61.220 124.420 66.040 ;
        RECT 124.220 65.840 124.420 66.040 ;
        RECT 66.620 66.635 66.820 66.925 ;
        RECT 66.620 53.615 66.820 53.905 ;
        RECT 66.620 53.660 66.820 53.860 ;
        RECT 66.620 53.660 66.820 66.880 ;
        RECT 66.620 66.680 66.820 66.880 ;
        RECT 74.300 33.875 74.500 34.165 ;
        RECT 74.300 33.920 74.500 34.120 ;
        RECT 74.300 33.920 74.500 37.060 ;
        RECT 74.300 36.815 74.500 37.105 ;
        RECT 74.300 36.860 74.500 37.060 ;
        RECT 71.900 59.075 72.100 59.365 ;
        RECT 71.900 56.555 72.100 56.845 ;
        RECT 71.900 56.600 72.100 56.800 ;
        RECT 71.900 56.600 72.100 59.320 ;
        RECT 71.900 59.120 72.100 59.320 ;
        RECT 101.660 59.075 101.860 59.365 ;
        RECT 101.660 56.975 101.860 57.265 ;
        RECT 101.660 57.020 101.860 57.220 ;
        RECT 101.660 57.020 101.860 59.320 ;
        RECT 101.660 59.120 101.860 59.320 ;
        RECT 92.540 103.595 92.740 103.885 ;
        RECT 92.540 37.655 92.740 37.945 ;
        RECT 92.540 37.700 92.740 37.900 ;
        RECT 92.540 37.700 92.740 103.840 ;
        RECT 92.540 103.640 92.740 103.840 ;
        RECT 75.740 110.735 75.940 111.025 ;
        RECT 75.740 72.515 75.940 72.805 ;
        RECT 75.740 72.560 75.940 72.760 ;
        RECT 75.740 72.560 75.940 110.980 ;
        RECT 75.740 110.780 75.940 110.980 ;
        RECT 74.300 103.595 74.500 103.885 ;
        RECT 74.300 65.375 74.500 65.665 ;
        RECT 74.300 65.420 74.500 65.620 ;
        RECT 74.300 65.420 74.500 103.840 ;
        RECT 74.300 103.640 74.500 103.840 ;
        RECT 100.630 89.245 100.970 89.675 ;
        RECT 100.625 89.245 100.975 89.675 ;
        RECT 100.620 89.280 100.980 89.640 ;
        RECT 104.055 89.315 104.265 89.605 ;
        RECT 104.060 64.115 104.260 64.405 ;
        RECT 104.060 64.160 104.260 64.360 ;
        RECT 104.060 64.160 104.260 89.560 ;
        RECT 104.060 89.360 104.260 89.560 ;
        RECT 97.820 80.915 98.020 81.205 ;
        RECT 97.820 68.315 98.020 68.605 ;
        RECT 97.820 68.360 98.020 68.560 ;
        RECT 97.820 68.360 98.020 81.160 ;
        RECT 97.820 80.960 98.020 81.160 ;
        RECT 85.340 106.955 85.540 107.245 ;
        RECT 85.340 72.515 85.540 72.805 ;
        RECT 85.340 72.560 85.540 72.760 ;
        RECT 85.340 72.560 85.540 107.200 ;
        RECT 85.340 107.000 85.540 107.200 ;
        RECT 81.500 103.595 81.700 103.885 ;
        RECT 81.500 48.155 81.700 48.445 ;
        RECT 81.500 48.200 81.700 48.400 ;
        RECT 81.500 48.200 81.700 103.840 ;
        RECT 81.500 103.640 81.700 103.840 ;
        RECT 103.100 89.315 103.300 89.605 ;
        RECT 103.100 72.935 103.300 73.225 ;
        RECT 103.100 72.980 103.300 73.180 ;
        RECT 103.100 72.980 103.300 89.560 ;
        RECT 103.100 89.360 103.300 89.560 ;
        RECT 102.620 111.995 102.820 112.285 ;
        RECT 102.620 94.355 102.820 94.645 ;
        RECT 102.620 94.400 102.820 94.600 ;
        RECT 102.620 94.400 102.820 112.240 ;
        RECT 102.620 112.040 102.820 112.240 ;
        RECT 98.780 127.115 98.980 127.405 ;
        RECT 98.780 84.275 98.980 84.565 ;
        RECT 98.780 84.320 98.980 84.520 ;
        RECT 98.780 84.320 98.980 127.360 ;
        RECT 98.780 127.160 98.980 127.360 ;
        RECT 112.220 119.555 112.420 119.845 ;
        RECT 112.220 108.635 112.420 108.925 ;
        RECT 112.220 108.680 112.420 108.880 ;
        RECT 112.220 108.680 112.420 119.800 ;
        RECT 112.220 119.600 112.420 119.800 ;
        RECT 84.380 126.275 84.580 126.565 ;
        RECT 84.380 117.455 84.580 117.745 ;
        RECT 84.380 117.500 84.580 117.700 ;
        RECT 84.380 117.500 84.580 126.520 ;
        RECT 84.380 126.320 84.580 126.520 ;
        RECT 96.860 127.115 97.060 127.405 ;
        RECT 96.860 117.455 97.060 117.745 ;
        RECT 96.860 117.500 97.060 117.700 ;
        RECT 96.860 117.500 97.060 127.360 ;
        RECT 96.860 127.160 97.060 127.360 ;
        RECT 101.660 119.555 101.860 119.845 ;
        RECT 101.660 117.455 101.860 117.745 ;
        RECT 101.660 117.500 101.860 117.700 ;
        RECT 101.660 117.500 101.860 119.800 ;
        RECT 101.660 119.600 101.860 119.800 ;
        RECT 112.220 127.115 112.420 127.405 ;
        RECT 112.220 124.595 112.420 124.885 ;
        RECT 112.220 124.640 112.420 124.840 ;
        RECT 112.220 124.640 112.420 127.360 ;
        RECT 112.220 127.160 112.420 127.360 ;
        RECT 71.420 71.675 71.620 71.965 ;
        RECT 71.420 71.720 71.620 71.920 ;
        RECT 71.420 71.720 71.620 110.140 ;
        RECT 71.420 109.895 71.620 110.185 ;
        RECT 71.420 109.940 71.620 110.140 ;
        RECT 71.420 20.435 71.620 20.725 ;
        RECT 71.420 20.480 71.620 20.680 ;
        RECT 71.420 20.480 71.620 53.860 ;
        RECT 71.420 26.315 71.620 26.605 ;
        RECT 71.420 26.360 71.620 26.560 ;
        RECT 71.420 53.615 71.620 53.905 ;
        RECT 71.420 53.660 71.620 53.860 ;
        RECT 98.780 27.575 98.980 27.865 ;
        RECT 98.780 26.315 98.980 26.605 ;
        RECT 98.780 26.360 98.980 26.560 ;
        RECT 98.780 26.360 98.980 27.820 ;
        RECT 98.780 27.620 98.980 27.820 ;
        RECT 103.580 26.315 103.780 26.605 ;
        RECT 103.580 26.360 103.780 26.560 ;
        RECT 103.580 26.360 103.780 27.820 ;
        RECT 103.580 27.575 103.780 27.865 ;
        RECT 103.580 27.620 103.780 27.820 ;
        RECT 137.660 30.095 137.860 30.385 ;
        RECT 137.660 27.995 137.860 28.285 ;
        RECT 137.660 28.040 137.860 28.240 ;
        RECT 137.660 28.040 137.860 30.340 ;
        RECT 137.660 30.140 137.860 30.340 ;
        RECT 155.900 27.995 156.100 28.285 ;
        RECT 155.900 28.040 156.100 28.240 ;
        RECT 155.900 28.040 156.100 30.340 ;
        RECT 155.900 30.095 156.100 30.385 ;
        RECT 155.900 30.140 156.100 30.340 ;
        RECT 91.580 38.495 91.780 38.785 ;
        RECT 91.580 29.675 91.780 29.965 ;
        RECT 91.580 29.720 91.780 29.920 ;
        RECT 91.580 29.720 91.780 38.740 ;
        RECT 91.580 38.540 91.780 38.740 ;
        RECT 85.750 27.925 86.090 28.355 ;
        RECT 85.745 27.925 86.095 28.355 ;
        RECT 85.740 27.960 86.100 28.320 ;
        RECT 93.975 27.995 94.185 28.285 ;
        RECT 93.980 28.040 94.180 28.240 ;
        RECT 93.980 28.040 94.180 29.080 ;
        RECT 93.980 28.835 94.180 29.125 ;
        RECT 93.980 28.880 94.180 29.080 ;
        RECT 69.980 96.035 70.180 96.325 ;
        RECT 69.980 48.995 70.180 49.285 ;
        RECT 69.980 49.040 70.180 49.240 ;
        RECT 69.980 49.040 70.180 96.280 ;
        RECT 69.980 96.080 70.180 96.280 ;
        RECT 69.980 96.080 70.180 108.040 ;
        RECT 69.980 107.795 70.180 108.085 ;
        RECT 69.980 107.840 70.180 108.040 ;
        RECT 111.260 103.595 111.460 103.885 ;
        RECT 111.260 103.640 111.460 103.840 ;
        RECT 111.260 103.640 111.460 108.040 ;
        RECT 111.260 106.535 111.460 106.825 ;
        RECT 111.260 106.580 111.460 106.780 ;
        RECT 111.260 107.795 111.460 108.085 ;
        RECT 111.260 107.840 111.460 108.040 ;
        RECT 120.860 103.595 121.060 103.885 ;
        RECT 120.860 103.640 121.060 103.840 ;
        RECT 120.860 103.640 121.060 106.780 ;
        RECT 120.860 106.535 121.060 106.825 ;
        RECT 120.860 106.580 121.060 106.780 ;
        RECT 130.460 85.955 130.660 86.245 ;
        RECT 130.460 86.000 130.660 86.200 ;
        RECT 130.460 86.000 130.660 103.840 ;
        RECT 130.460 103.595 130.660 103.885 ;
        RECT 130.460 103.640 130.660 103.840 ;
        RECT 142.460 65.795 142.660 66.085 ;
        RECT 142.460 65.840 142.660 66.040 ;
        RECT 142.460 65.840 142.660 68.140 ;
        RECT 142.460 67.895 142.660 68.185 ;
        RECT 142.460 67.940 142.660 68.140 ;
        RECT 77.660 71.675 77.860 71.965 ;
        RECT 77.660 50.675 77.860 50.965 ;
        RECT 77.660 50.720 77.860 50.920 ;
        RECT 77.660 50.720 77.860 71.920 ;
        RECT 77.660 71.720 77.860 71.920 ;
        RECT 90.615 43.115 90.825 43.405 ;
        RECT 90.620 41.015 90.820 41.305 ;
        RECT 90.620 41.060 90.820 41.260 ;
        RECT 90.620 41.060 90.820 43.360 ;
        RECT 90.620 43.160 90.820 43.360 ;
        RECT 100.150 43.045 100.490 43.475 ;
        RECT 100.145 43.045 100.495 43.475 ;
        RECT 100.140 43.080 100.500 43.440 ;
        RECT 102.135 80.075 102.345 80.365 ;
        RECT 102.140 77.555 102.340 77.845 ;
        RECT 102.140 77.600 102.340 77.800 ;
        RECT 102.140 77.600 102.340 80.320 ;
        RECT 102.140 80.120 102.340 80.320 ;
        RECT 117.980 80.915 118.180 81.205 ;
        RECT 117.975 80.075 118.185 80.365 ;
        RECT 117.980 80.120 118.180 80.320 ;
        RECT 117.980 80.120 118.180 81.160 ;
        RECT 117.980 80.960 118.180 81.160 ;
        RECT 134.780 65.795 134.980 66.085 ;
        RECT 134.780 48.995 134.980 49.285 ;
        RECT 134.780 49.040 134.980 49.240 ;
        RECT 134.780 49.040 134.980 66.040 ;
        RECT 134.780 65.840 134.980 66.040 ;
        RECT 58.460 65.795 58.660 66.085 ;
        RECT 58.460 51.935 58.660 52.225 ;
        RECT 58.460 51.980 58.660 52.180 ;
        RECT 58.460 51.980 58.660 66.040 ;
        RECT 58.460 65.840 58.660 66.040 ;
        RECT 58.460 65.840 58.660 98.380 ;
        RECT 58.460 98.135 58.660 98.425 ;
        RECT 58.460 98.180 58.660 98.380 ;
        RECT 186.620 122.075 186.820 122.365 ;
        RECT 186.620 122.120 186.820 122.320 ;
        RECT 186.620 122.120 186.820 154.240 ;
        RECT 186.620 154.040 187.300 154.240 ;
        RECT 187.100 154.040 187.300 154.240 ;
        RECT 182.780 138.035 182.980 138.325 ;
        RECT 182.780 138.080 182.980 138.280 ;
        RECT 182.780 138.080 182.980 154.240 ;
        RECT 182.780 154.040 183.460 154.240 ;
        RECT 183.260 154.040 183.460 154.240 ;
        RECT 56.540 154.040 57.220 154.240 ;
        RECT 56.540 154.040 56.740 154.240 ;
        RECT 57.020 135.095 57.220 135.385 ;
        RECT 57.020 135.140 57.220 135.340 ;
        RECT 57.020 135.140 57.220 154.240 ;
        RECT 52.220 154.040 52.900 154.240 ;
        RECT 52.220 153.995 52.420 154.285 ;
        RECT 52.220 154.040 52.420 154.240 ;
        RECT 52.700 154.040 52.900 154.240 ;
        RECT 48.860 154.040 49.540 154.240 ;
        RECT 48.860 154.040 49.060 154.240 ;
        RECT 49.340 153.995 49.540 154.285 ;
        RECT 49.340 154.040 49.540 154.240 ;
        RECT 45.020 154.040 45.700 154.240 ;
        RECT 45.020 154.040 45.220 154.240 ;
        RECT 45.500 153.995 45.700 154.285 ;
        RECT 45.500 154.040 45.700 154.240 ;
        RECT 41.180 154.040 41.860 154.240 ;
        RECT 41.180 154.040 41.380 154.240 ;
        RECT 41.660 153.995 41.860 154.285 ;
        RECT 41.660 154.040 41.860 154.240 ;
        RECT 37.340 154.040 38.020 154.240 ;
        RECT 37.340 154.040 37.540 154.240 ;
        RECT 37.820 153.995 38.020 154.285 ;
        RECT 37.820 154.040 38.020 154.240 ;
        RECT 33.020 154.040 33.700 154.240 ;
        RECT 33.020 153.995 33.220 154.285 ;
        RECT 33.020 154.040 33.220 154.240 ;
        RECT 33.500 154.040 33.700 154.240 ;
        RECT 29.180 154.040 29.860 154.240 ;
        RECT 29.180 153.995 29.380 154.285 ;
        RECT 29.180 154.040 29.380 154.240 ;
        RECT 29.660 154.040 29.860 154.240 ;
        RECT 86.780 154.040 87.460 154.240 ;
        RECT 86.780 153.995 86.980 154.285 ;
        RECT 86.780 154.040 86.980 154.240 ;
        RECT 87.260 154.040 87.460 154.240 ;
        RECT 83.420 154.040 84.100 154.240 ;
        RECT 83.420 154.040 83.620 154.240 ;
        RECT 83.900 140.135 84.100 140.425 ;
        RECT 83.900 140.180 84.100 140.380 ;
        RECT 83.900 140.180 84.100 154.240 ;
        RECT 79.580 154.040 80.260 154.240 ;
        RECT 79.580 154.040 79.780 154.240 ;
        RECT 80.060 153.995 80.260 154.285 ;
        RECT 80.060 154.040 80.260 154.240 ;
        RECT 75.740 154.040 76.420 154.240 ;
        RECT 75.740 154.040 75.940 154.240 ;
        RECT 76.220 153.995 76.420 154.285 ;
        RECT 76.220 154.040 76.420 154.240 ;
        RECT 71.420 154.040 72.100 154.240 ;
        RECT 71.420 153.995 71.620 154.285 ;
        RECT 71.420 154.040 71.620 154.240 ;
        RECT 71.900 154.040 72.100 154.240 ;
        RECT 67.580 154.040 68.260 154.240 ;
        RECT 67.580 153.995 67.780 154.285 ;
        RECT 67.580 154.040 67.780 154.240 ;
        RECT 68.060 154.040 68.260 154.240 ;
        RECT 63.740 154.040 64.420 154.240 ;
        RECT 63.740 146.435 63.940 146.725 ;
        RECT 63.740 146.480 63.940 146.680 ;
        RECT 63.740 146.480 63.940 154.240 ;
        RECT 64.220 154.040 64.420 154.240 ;
        RECT 59.900 154.040 60.580 154.240 ;
        RECT 59.900 153.575 60.100 153.865 ;
        RECT 59.900 153.620 60.100 153.820 ;
        RECT 59.900 153.620 60.100 154.240 ;
        RECT 60.380 154.040 60.580 154.240 ;
        RECT 117.500 154.040 118.180 154.240 ;
        RECT 117.500 153.995 117.700 154.285 ;
        RECT 117.500 154.040 117.700 154.240 ;
        RECT 117.980 154.040 118.180 154.240 ;
        RECT 113.660 154.040 114.340 154.240 ;
        RECT 113.660 153.995 113.860 154.285 ;
        RECT 113.660 154.040 113.860 154.240 ;
        RECT 114.140 154.040 114.340 154.240 ;
        RECT 109.820 154.040 110.500 154.240 ;
        RECT 109.820 153.995 110.020 154.285 ;
        RECT 109.820 154.040 110.020 154.240 ;
        RECT 110.300 154.040 110.500 154.240 ;
        RECT 105.980 154.040 106.660 154.240 ;
        RECT 105.980 153.995 106.180 154.285 ;
        RECT 105.980 154.040 106.180 154.240 ;
        RECT 106.460 154.040 106.660 154.240 ;
        RECT 102.620 154.040 103.300 154.240 ;
        RECT 102.620 154.040 102.820 154.240 ;
        RECT 103.100 153.995 103.300 154.285 ;
        RECT 103.100 154.040 103.300 154.240 ;
        RECT 98.300 154.040 98.980 154.240 ;
        RECT 98.300 139.295 98.500 139.585 ;
        RECT 98.300 139.340 98.500 139.540 ;
        RECT 98.300 139.340 98.500 154.240 ;
        RECT 98.780 154.040 98.980 154.240 ;
        RECT 94.940 154.040 95.620 154.240 ;
        RECT 94.940 154.040 95.140 154.240 ;
        RECT 95.420 153.155 95.620 153.445 ;
        RECT 95.420 153.200 95.620 153.400 ;
        RECT 95.420 153.200 95.620 154.240 ;
        RECT 90.620 154.040 91.300 154.240 ;
        RECT 90.620 153.995 90.820 154.285 ;
        RECT 90.620 154.040 90.820 154.240 ;
        RECT 91.100 154.040 91.300 154.240 ;
      LAYER Metal5 ;
        RECT 15.515 3.470 179.125 151.510 ;
      LAYER TopMetal1 ;
        RECT 15.380 3.560 17.580 151.830 ;
        RECT 54.250 3.560 56.450 151.830 ;
        RECT 93.120 3.560 95.320 151.830 ;
        RECT 131.990 3.560 134.190 151.830 ;
        RECT 170.860 3.560 173.060 151.830 ;
        RECT 21.580 3.150 23.780 151.420 ;
        RECT 60.450 3.150 62.650 151.420 ;
        RECT 99.320 3.150 101.520 151.420 ;
        RECT 138.190 3.150 140.390 151.420 ;
        RECT 177.060 3.150 179.260 151.420 ;
  END
END tt_um_microlane_demo
END LIBRARY

